One B-rep face of a CAD part: STEP entity #882.
In plain terms, the planar face has unit normal (1, 0, 0).
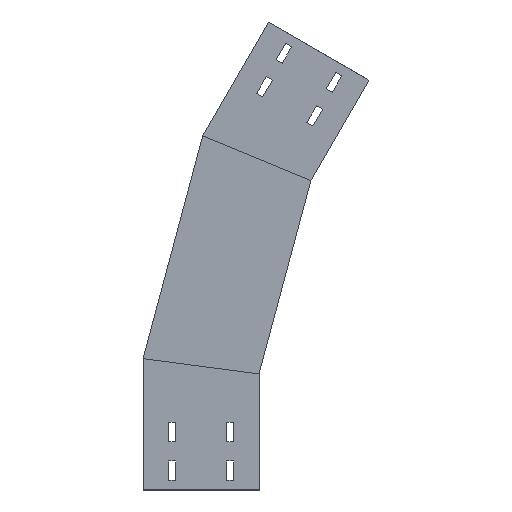
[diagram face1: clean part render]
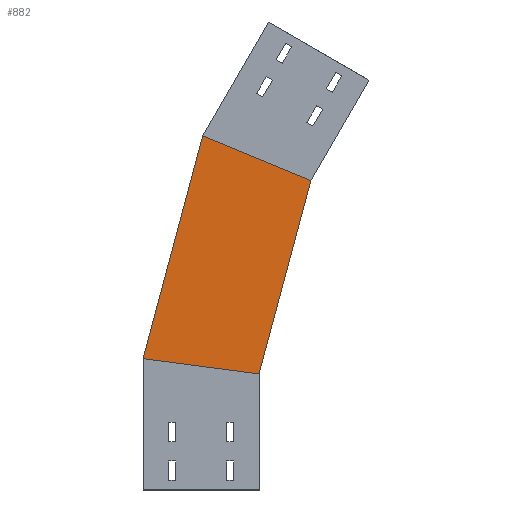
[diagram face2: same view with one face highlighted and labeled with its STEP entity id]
Its self-contained STEP definition (entity closure, numbers rounded to 3 decimals):
#76 = DIRECTION ( 'NONE',  ( 0., -0.991, -0.131 ) ) ;
#78 = DIRECTION ( 'NONE',  ( 0., -0.924, -0.383 ) ) ;
#119 = EDGE_LOOP ( 'NONE', ( #1549, #1663, #1514, #267 ) ) ;
#171 = CARTESIAN_POINT ( 'NONE',  ( 0., -67.034, 400.175 ) ) ;
#210 = CARTESIAN_POINT ( 'NONE',  ( 0., -19.411, 147.444 ) ) ;
#267 = ORIENTED_EDGE ( 'NONE', *, *, #1376, .F. ) ;
#330 = DIRECTION ( 'NONE',  ( 0., -0.259, 0.966 ) ) ;
#348 = VECTOR ( 'NONE', #760, 1000. ) ;
#449 = VECTOR ( 'NONE', #78, 1000. ) ;
#479 = CARTESIAN_POINT ( 'NONE',  ( 0., 5.648, 128.921 ) ) ;
#532 = CARTESIAN_POINT ( 'NONE',  ( 0., -100.899, 386.148 ) ) ;
#699 = VECTOR ( 'NONE', #330, 1000. ) ;
#760 = DIRECTION ( 'NONE',  ( 0., -0.259, 0.966 ) ) ;
#882 = ADVANCED_FACE ( 'NONE', ( #1499 ), #1937, .T. ) ;
#894 = CARTESIAN_POINT ( 'NONE',  ( 0., 150., 169.748 ) ) ;
#1010 = EDGE_CURVE ( 'NONE', #1445, #2034, #1470, .T. ) ;
#1075 = CARTESIAN_POINT ( 'NONE',  ( 0., 150.537, 167.744 ) ) ;
#1178 = CARTESIAN_POINT ( 'NONE',  ( 0., 5.648, 128.921 ) ) ;
#1238 = EDGE_CURVE ( 'NONE', #1561, #2034, #1404, .T. ) ;
#1342 = DIRECTION ( 'NONE',  ( 1., 0., 0. ) ) ;
#1348 = CARTESIAN_POINT ( 'NONE',  ( 0., 72.744, 458.073 ) ) ;
#1376 = EDGE_CURVE ( 'NONE', #1919, #1561, #1498, .T. ) ;
#1404 = LINE ( 'NONE', #479, #699 ) ;
#1413 = LINE ( 'NONE', #1075, #348 ) ;
#1445 = VERTEX_POINT ( 'NONE', #1348 ) ;
#1470 = LINE ( 'NONE', #532, #449 ) ;
#1498 = LINE ( 'NONE', #210, #1978 ) ;
#1499 = FACE_OUTER_BOUND ( 'NONE', #119, .T. ) ;
#1514 = ORIENTED_EDGE ( 'NONE', *, *, #1238, .F. ) ;
#1549 = ORIENTED_EDGE ( 'NONE', *, *, #2032, .T. ) ;
#1561 = VERTEX_POINT ( 'NONE', #2031 ) ;
#1663 = ORIENTED_EDGE ( 'NONE', *, *, #1010, .T. ) ;
#1712 = AXIS2_PLACEMENT_3D ( 'NONE', #1178, #1342, #1786 ) ;
#1786 = DIRECTION ( 'NONE',  ( 0., 0., -1. ) ) ;
#1919 = VERTEX_POINT ( 'NONE', #894 ) ;
#1937 = PLANE ( 'NONE',  #1712 ) ;
#1978 = VECTOR ( 'NONE', #76, 1000. ) ;
#2031 = CARTESIAN_POINT ( 'NONE',  ( 0., 0., 150. ) ) ;
#2032 = EDGE_CURVE ( 'NONE', #1919, #1445, #1413, .T. ) ;
#2034 = VERTEX_POINT ( 'NONE', #171 ) ;
